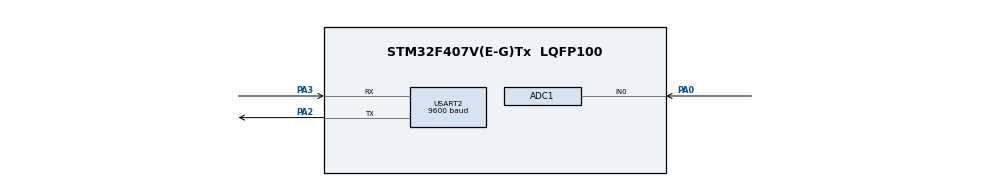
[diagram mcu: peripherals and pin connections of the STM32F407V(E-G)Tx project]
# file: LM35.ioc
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ADC1.Channel-1\#ChannelRegularConversion=ADC_CHANNEL_0
ADC1.NbrOfConversionFlag=1
ADC1.Rank-1\#ChannelRegularConversion=1
ADC1.SamplingTime-1\#ChannelRegularConversion=ADC_SAMPLETIME_3CYCLES
ADC1.master=1
Mcu.Family=STM32F4
Mcu.Name=STM32F407V(E-G)Tx
Mcu.Package=LQFP100
NVIC.ADC_IRQn=true\:0\:0\:false\:false\:true\:true\:true\:true
NVIC.PriorityGroup=NVIC_PRIORITYGROUP_0
NVIC.USART2_IRQn=true\:0\:0\:false\:false\:true\:true\:true\:true
PA0-WKUP.Signal=ADCx_IN0
PA2.Mode=Asynchronous
PA2.Signal=USART2_TX
PA3.Mode=Asynchronous
PA3.Signal=USART2_RX
ProjectManager.HeapSize=0x200
ProjectManager.StackSize=0x400
ProjectManager.TargetToolchain=STM32CubeIDE
RCC.48MHZClocksFreq_Value=14285714.285714285
RCC.AHBFreq_Value=25000000
RCC.APB1CLKDivider=RCC_HCLK_DIV8
RCC.APB1Freq_Value=3125000
RCC.APB1TimFreq_Value=6250000
RCC.APB2CLKDivider=RCC_HCLK_DIV2
RCC.APB2Freq_Value=12500000
RCC.APB2TimFreq_Value=25000000
RCC.CortexFreq_Value=25000000
RCC.HCLKFreq_Value=25000000
RCC.HSE_VALUE=8000000
RCC.HSI_VALUE=16000000
RCC.PLLM=8
RCC.PLLN=50
RCC.PLLP=RCC_PLLP_DIV4
RCC.PLLQ=7
RCC.SYSCLKFreq_VALUE=25000000
RCC.SYSCLKSource=RCC_SYSCLKSOURCE_PLLCLK
RCC.VCOOutputFreq_Value=100000000
SH.ADCx_IN0.0=ADC1_IN0,IN0
USART2.BaudRate=9600
USART2.VirtualMode=VM_ASYNC
board=STM32F407G-DISC1

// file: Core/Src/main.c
/* USER CODE BEGIN Header */
/**
  ******************************************************************************
  * @file           : main.c
  * @brief          : LM35 Temperature Sensor using ADC + UART2
  ******************************************************************************
  */
 /* USER CODE END Header */

#include "main.h"
#include <stdio.h>
#include <string.h>

ADC_HandleTypeDef hadc1;
UART_HandleTypeDef huart2;

void SystemClock_Config(void);
static void MX_GPIO_Init(void);
static void MX_ADC1_Init(void);
static void MX_USART2_UART_Init(void);

int main(void)
{
  char msg[50];
  uint32_t adc_val;
  float voltage, temperature;

  HAL_Init();
  SystemClock_Config();

  MX_GPIO_Init();
  MX_ADC1_Init();
  MX_USART2_UART_Init();

  while (1)
  {
    /* Start ADC Conversion */
    HAL_ADC_Start(&hadc1);
    HAL_ADC_PollForConversion(&hadc1, HAL_MAX_DELAY);
    adc_val = HAL_ADC_GetValue(&hadc1);
    HAL_ADC_Stop(&hadc1);

    /* Convert ADC to Voltage */
    voltage = (adc_val * 3.3f) / 4095.0f;

    /* Convert Voltage to Temperature */
    temperature = voltage * 100.0f;

    /* Send Data via UART */
    sprintf(msg, "Temp: %.2f C\r\n", temperature);
    HAL_UART_Transmit(&huart2, (uint8_t *)msg, strlen(msg), HAL_MAX_DELAY);

    HAL_Delay(1000);
  }
}

/* ---------------- System Clock ---------------- */
void SystemClock_Config(void)
{
  RCC_OscInitTypeDef RCC_OscInitStruct = {0};
  RCC_ClkInitTypeDef RCC_ClkInitStruct = {0};

  __HAL_RCC_PWR_CLK_ENABLE();
  __HAL_PWR_VOLTAGESCALING_CONFIG(PWR_REGULATOR_VOLTAGE_SCALE1);

  RCC_OscInitStruct.OscillatorType = RCC_OSCILLATORTYPE_HSI;
  RCC_OscInitStruct.HSIState = RCC_HSI_ON;
  RCC_OscInitStruct.PLL.PLLState = RCC_PLL_ON;
  RCC_OscInitStruct.PLL.PLLSource = RCC_PLLSOURCE_HSI;
  RCC_OscInitStruct.PLL.PLLM = 8;
  RCC_OscInitStruct.PLL.PLLN = 50;
  RCC_OscInitStruct.PLL.PLLP = RCC_PLLP_DIV2;
  RCC_OscInitStruct.PLL.PLLQ = 7;
  HAL_RCC_OscConfig(&RCC_OscInitStruct);

  RCC_ClkInitStruct.ClockType = RCC_CLOCKTYPE_HCLK | RCC_CLOCKTYPE_SYSCLK
                              | RCC_CLOCKTYPE_PCLK1 | RCC_CLOCKTYPE_PCLK2;
  RCC_ClkInitStruct.SYSCLKSource = RCC_SYSCLKSOURCE_PLLCLK;
  RCC_ClkInitStruct.AHBCLKDivider = RCC_SYSCLK_DIV1;
  RCC_ClkInitStruct.APB1CLKDivider = RCC_HCLK_DIV8;
  RCC_ClkInitStruct.APB2CLKDivider = RCC_HCLK_DIV2;
  HAL_RCC_ClockConfig(&RCC_ClkInitStruct, FLASH_LATENCY_1);
}

/* ---------------- ADC1 Init ---------------- */
static void MX_ADC1_Init(void)
{
  ADC_ChannelConfTypeDef sConfig = {0};

  hadc1.Instance = ADC1;
  hadc1.Init.Resolution = ADC_RESOLUTION_12B;
  hadc1.Init.ScanConvMode = DISABLE;
  hadc1.Init.ContinuousConvMode = DISABLE;
  hadc1.Init.DataAlign = ADC_DATAALIGN_RIGHT;
  hadc1.Init.NbrOfConversion = 1;
  HAL_ADC_Init(&hadc1);

  sConfig.Channel = ADC_CHANNEL_0;      // PA0
  sConfig.Rank = 1;
  sConfig.SamplingTime = ADC_SAMPLETIME_56CYCLES;
  HAL_ADC_ConfigChannel(&hadc1, &sConfig);
}

/* ---------------- UART2 Init ---------------- */
static void MX_USART2_UART_Init(void)
{
  huart2.Instance = USART2;
  huart2.Init.BaudRate = 9600;
  huart2.Init.WordLength = UART_WORDLENGTH_8B;
  huart2.Init.StopBits = UART_STOPBITS_1;
  huart2.Init.Parity = UART_PARITY_NONE;
  huart2.Init.Mode = UART_MODE_TX_RX;
  HAL_UART_Init(&huart2);
}

/* ---------------- GPIO Init ---------------- */
static void MX_GPIO_Init(void)
{
  __HAL_RCC_GPIOA_CLK_ENABLE();
}

/* ---------------- Error Handler ---------------- */
void Error_Handler(void)
{
  __disable_irq();
  while (1);
}
